VERSION 5.5 ;
NAMESCASESENSITIVE ON ;
BUSBITCHARS "[]" ;
DIVIDERCHAR "/" ;

PROPERTYDEFINITIONS
  LAYER routingPitch REAL ;
END PROPERTYDEFINITIONS

UNITS
  DATABASE MICRONS 1000 ;
END UNITS
MANUFACTURINGGRID 0.01 ;
LAYER POLY1
  TYPE MASTERSLICE ;
END POLY1

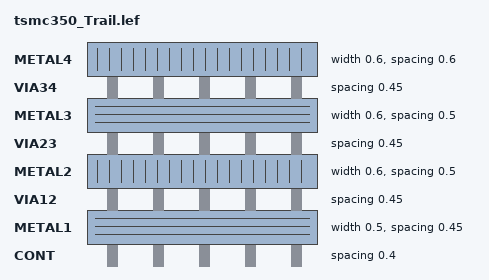
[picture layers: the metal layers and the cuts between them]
LAYER CONT
  TYPE CUT ;
  SPACING 0.4 ;
END CONT

LAYER METAL1
  TYPE ROUTING ;
  DIRECTION HORIZONTAL ;
  PITCH 0 ;
  WIDTH 0.5 ;
  SPACING 0.45 ;
  PROPERTY routingPitch 1.25 ;
END METAL1

LAYER VIA12
  TYPE CUT ;
  SPACING 0.45 ;
END VIA12

LAYER METAL2
  TYPE ROUTING ;
  DIRECTION VERTICAL ;
  PITCH 0 ;
  WIDTH 0.6 ;
  SPACING 0.5 ;
  PROPERTY routingPitch 1.4 ;
END METAL2

LAYER VIA23
  TYPE CUT ;
  SPACING 0.45 ;
END VIA23

LAYER METAL3
  TYPE ROUTING ;
  DIRECTION HORIZONTAL ;
  PITCH 0 ;
  WIDTH 0.6 ;
  SPACING 0.5 ;
  PROPERTY routingPitch 1.25 ;
END METAL3

LAYER VIA34
  TYPE CUT ;
  SPACING 0.45 ;
END VIA34

LAYER METAL4
  TYPE ROUTING ;
  DIRECTION VERTICAL ;
  PITCH 0 ;
  WIDTH 0.6 ;
  SPACING 0.6 ;
  PROPERTY routingPitch 1.4 ;
END METAL4

LAYER OVERLAP
  TYPE OVERLAP ;
END OVERLAP

VIARULE M4_M3 GENERATE
  LAYER METAL3 ;
    ENCLOSURE 0.2 0.2 ;
  LAYER METAL4 ;
    ENCLOSURE 0.15 0.15 ;
  LAYER VIA34 ;
    RECT -0.25 -0.25 0.25 0.25 ;
    SPACING 1 BY 1 ;
END M4_M3

VIARULE M3_M2 GENERATE
  LAYER METAL2 ;
    ENCLOSURE 0.2 0.2 ;
  LAYER METAL3 ;
    ENCLOSURE 0.15 0.15 ;
  LAYER VIA23 ;
    RECT -0.25 -0.25 0.25 0.25 ;
    SPACING 1 BY 1 ;
END M3_M2

VIARULE M2_M1 GENERATE
  LAYER METAL1 ;
    ENCLOSURE 0.2 0.2 ;
  LAYER METAL2 ;
    ENCLOSURE 0.15 0.15 ;
  LAYER VIA12 ;
    RECT -0.25 -0.25 0.25 0.25 ;
    SPACING 1 BY 1 ;
END M2_M1

VIARULE M1_POLY1 GENERATE
  LAYER POLY1 ;
    ENCLOSURE 0.2 0.2 ;
  LAYER METAL1 ;
    ENCLOSURE 0.15 0.15 ;
  LAYER CONT ;
    RECT -0.2 -0.2 0.2 0.2 ;
    SPACING 1 BY 1 ;
END M1_POLY1

VIA M1_POLY1
  LAYER CONT ;
    RECT -0.2 -0.2 0.2 0.2 ;
  LAYER POLY1 ;
    RECT -0.4 -0.4 0.4 0.4 ;
  LAYER METAL1 ;
    RECT -0.35 -0.35 0.35 0.35 ;
END M1_POLY1

VIA M2_M1
  LAYER VIA12 ;
    RECT -0.25 -0.25 0.25 0.25 ;
  LAYER METAL2 ;
    RECT -0.4 -0.4 0.4 0.4 ;
  LAYER METAL1 ;
    RECT -0.45 -0.45 0.45 0.45 ;
END M2_M1

VIA M3_M2
  LAYER VIA23 ;
    RECT -0.25 -0.25 0.25 0.25 ;
  LAYER METAL3 ;
    RECT -0.4 -0.4 0.4 0.4 ;
  LAYER METAL2 ;
    RECT -0.45 -0.45 0.45 0.45 ;
END M3_M2

VIA M4_M3
  LAYER VIA34 ;
    RECT -0.25 -0.25 0.25 0.25 ;
  LAYER METAL4 ;
    RECT -0.4 -0.4 0.4 0.4 ;
  LAYER METAL3 ;
    RECT -0.45 -0.45 0.45 0.45 ;
END M4_M3


MACRO TSMC350nm_TA2Cell_NoFG
  PIN VIN2_MINUS
    DIRECTION INOUT ;
    USE SIGNAL ;
    PORT
      LAYER METAL1 ;
        RECT 0.0 4.9 1.4 6.3 ;
    END
  END VIN2_MINUS
  PIN VD_P<0>
    DIRECTION INOUT ;
    USE SIGNAL ;
    PORT
      LAYER METAL1 ;
        RECT 0.0 16.1 1.4 17.5 ;
    END
  END VD_P<0>
  PIN OUTPUT<0>
    DIRECTION INOUT ;
    USE SIGNAL ;
    PORT
      LAYER METAL1 ;
        RECT 103.6 11.9 105.0 13.3 ;
    END
  END OUTPUT<0>
  PIN VD_P<1>
    DIRECTION INOUT ;
    USE SIGNAL ;
    PORT
      LAYER METAL1 ;
        RECT 0.0 0.7 1.395 2.1 ;
    END
  END VD_P<1>
  PIN VIN1_MINUS
    DIRECTION INOUT ;
    USE SIGNAL ;
    PORT
      LAYER METAL1 ;
        RECT 0.0 10.5 1.4 11.9 ;
    END
  END VIN1_MINUS
  PIN VIN1_PLUS
    DIRECTION INOUT ;
    USE SIGNAL ;
    PORT
      LAYER METAL1 ;
        RECT 0.0 13.3 1.4 14.7 ;
    END
  END VIN1_PLUS
  PIN VIN2_PLUS
    DIRECTION INOUT ;
    USE SIGNAL ;
    PORT
      LAYER METAL1 ;
        RECT 0.0 7.7 1.4 9.1 ;
    END
  END VIN2_PLUS
  PIN OUTPUT<1>
    DIRECTION INOUT ;
    USE SIGNAL ;
    PORT
      LAYER METAL1 ;
        RECT 103.6 7.7 105.0 9.1 ;
    END
  END OUTPUT<1>
  PIN VPWR_b
    DIRECTION INOUT ;
    USE SIGNAL ;
    PORT
      LAYER METAL2 ;
        RECT 93.1 0.0 94.5 1.4 ;
    END
  END VPWR_b
  PIN GND_b
    DIRECTION INOUT ;
    USE SIGNAL ;
    PORT
      LAYER METAL2 ;
        RECT 79.1 0.0 80.5 1.4 ;
    END
  END GND_b
  PIN VINJ_b
    DIRECTION INOUT ;
    USE SIGNAL ;
    PORT
      LAYER METAL2 ;
        RECT 44.1 0.0 45.5 1.4 ;
    END
  END VINJ_b
  PIN Vsel_b
    DIRECTION INOUT ;
    USE SIGNAL ;
    PORT
      LAYER METAL2 ;
        RECT 38.5 0.0 39.9 1.4 ;
    END
  END Vsel_b
  PIN Vsel
    DIRECTION INOUT ;
    USE SIGNAL ;
    PORT
      LAYER METAL2 ;
        RECT 38.5 20.6 39.9 22.0 ;
    END
  END Vsel
  PIN Vg_b
    DIRECTION INOUT ;
    USE SIGNAL ;
    PORT
      LAYER METAL2 ;
        RECT 10.5 0.0 11.9 1.4 ;
    END
  END Vg_b
  PIN VTUN
    DIRECTION INOUT ;
    USE SIGNAL ;
    PORT
      LAYER METAL2 ;
        RECT 2.1 20.605 3.5 22.0 ;
    END
  END VTUN
  PIN VINJ
    DIRECTION INOUT ;
    USE SIGNAL ;
    PORT
      LAYER METAL2 ;
        RECT 44.1 20.6 45.5 22.0 ;
    END
  END VINJ
  PIN VPWR
    DIRECTION INOUT ;
    USE SIGNAL ;
    PORT
      LAYER METAL2 ;
        RECT 93.1 20.6 94.5 22.0 ;
    END
  END VPWR
  PIN GND
    DIRECTION INOUT ;
    USE SIGNAL ;
    PORT
      LAYER METAL2 ;
        RECT 79.1 20.6 80.5 22.0 ;
    END
  END GND
  PIN VTUN_b
    DIRECTION INOUT ;
    USE SIGNAL ;
    PORT
      LAYER METAL2 ;
        RECT 2.1 0.0 3.5 1.395 ;
    END
  END VTUN_b
  PIN Vg
    DIRECTION INOUT ;
    USE SIGNAL ;
    PORT
      LAYER METAL2 ;
        RECT 10.5 20.6 11.9 22.0 ;
    END
  END Vg
END TSMC350nm_TA2Cell_NoFG

MACRO tile_analog_frame
  PIN n_Vg<0>
    DIRECTION INOUT ;
    USE SIGNAL ;
    PORT
      LAYER METAL3 ;
        RECT 3.64 225.2 5.04 228.0 ;
    END
  END n_Vg<0>
  PIN n_Vg<1>
    DIRECTION INOUT ;
    USE SIGNAL ;
    PORT
      LAYER METAL3 ;
        RECT 7.98 225.2 9.38 228.0 ;
    END
  END n_Vg<1>
  PIN n_Vg<2>
    DIRECTION INOUT ;
    USE SIGNAL ;
    PORT
      LAYER METAL3 ;
        RECT 12.32 225.2 13.72 228.0 ;
    END
  END n_Vg<2>
  PIN n_Vg<3>
    DIRECTION INOUT ;
    USE SIGNAL ;
    PORT
      LAYER METAL3 ;
        RECT 16.66 225.2 18.06 228.0 ;
    END
  END n_Vg<3>
  PIN n_Vg<4>
    DIRECTION INOUT ;
    USE SIGNAL ;
    PORT
      LAYER METAL3 ;
        RECT 21.0 225.2 22.4 228.0 ;
    END
  END n_Vg<4>
  PIN n_Vg<5>
    DIRECTION INOUT ;
    USE SIGNAL ;
    PORT
      LAYER METAL3 ;
        RECT 25.34 225.2 26.74 228.0 ;
    END
  END n_Vg<5>
  PIN n_Vg<6>
    DIRECTION INOUT ;
    USE SIGNAL ;
    PORT
      LAYER METAL3 ;
        RECT 29.68 225.2 31.08 228.0 ;
    END
  END n_Vg<6>
  PIN n_Vg<7>
    DIRECTION INOUT ;
    USE SIGNAL ;
    PORT
      LAYER METAL3 ;
        RECT 34.02 225.2 35.42 228.0 ;
    END
  END n_Vg<7>
  PIN n_Vg<8>
    DIRECTION INOUT ;
    USE SIGNAL ;
    PORT
      LAYER METAL3 ;
        RECT 38.36 225.2 39.76 228.0 ;
    END
  END n_Vg<8>
  PIN n_Vsel<0>
    DIRECTION INOUT ;
    USE SIGNAL ;
    PORT
      LAYER METAL3 ;
        RECT 42.7 225.2 44.1 228.0 ;
    END
  END n_Vsel<0>
  PIN n_Vsel<1>
    DIRECTION INOUT ;
    USE SIGNAL ;
    PORT
      LAYER METAL3 ;
        RECT 47.04 225.2 48.44 228.0 ;
    END
  END n_Vsel<1>
  PIN n_Vsel<2>
    DIRECTION INOUT ;
    USE SIGNAL ;
    PORT
      LAYER METAL3 ;
        RECT 51.38 225.2 52.78 228.0 ;
    END
  END n_Vsel<2>
  PIN n_Vsel<3>
    DIRECTION INOUT ;
    USE SIGNAL ;
    PORT
      LAYER METAL3 ;
        RECT 55.72 225.2 57.12 228.0 ;
    END
  END n_Vsel<3>
  PIN n_Vsel<4>
    DIRECTION INOUT ;
    USE SIGNAL ;
    PORT
      LAYER METAL3 ;
        RECT 60.06 225.2 61.46 228.0 ;
    END
  END n_Vsel<4>
  PIN n_Vsel<5>
    DIRECTION INOUT ;
    USE SIGNAL ;
    PORT
      LAYER METAL3 ;
        RECT 64.4 225.2 65.8 228.0 ;
    END
  END n_Vsel<5>
  PIN n_Vsel<6>
    DIRECTION INOUT ;
    USE SIGNAL ;
    PORT
      LAYER METAL3 ;
        RECT 68.74 225.2 70.14 228.0 ;
    END
  END n_Vsel<6>
  PIN n_Vsel<7>
    DIRECTION INOUT ;
    USE SIGNAL ;
    PORT
      LAYER METAL3 ;
        RECT 73.08 225.2 74.48 228.0 ;
    END
  END n_Vsel<7>
  PIN n_Vsel<8>
    DIRECTION INOUT ;
    USE SIGNAL ;
    PORT
      LAYER METAL3 ;
        RECT 77.42 225.2 78.82 228.0 ;
    END
  END n_Vsel<8>
  PIN e_Output<0>
    DIRECTION INOUT ;
    USE SIGNAL ;
    PORT
      LAYER METAL3 ;
        RECT 402.2 222.26 405.0 223.66 ;
    END
  END e_Output<0>
  PIN e_Output<1>
    DIRECTION INOUT ;
    USE SIGNAL ;
    PORT
      LAYER METAL3 ;
        RECT 402.2 217.92 405.0 219.32 ;
    END
  END e_Output<1>
  PIN e_Output<2>
    DIRECTION INOUT ;
    USE SIGNAL ;
    PORT
      LAYER METAL3 ;
        RECT 402.2 213.58 405.0 214.98 ;
    END
  END e_Output<2>
  PIN e_Output<3>
    DIRECTION INOUT ;
    USE SIGNAL ;
    PORT
      LAYER METAL3 ;
        RECT 402.2 209.24 405.0 210.64 ;
    END
  END e_Output<3>
  PIN e_Output<4>
    DIRECTION INOUT ;
    USE SIGNAL ;
    PORT
      LAYER METAL3 ;
        RECT 402.2 204.9 405.0 206.3 ;
    END
  END e_Output<4>
  PIN e_Output<5>
    DIRECTION INOUT ;
    USE SIGNAL ;
    PORT
      LAYER METAL3 ;
        RECT 402.2 200.56 405.0 201.96 ;
    END
  END e_Output<5>
  PIN e_Output<6>
    DIRECTION INOUT ;
    USE SIGNAL ;
    PORT
      LAYER METAL3 ;
        RECT 402.2 196.22 405.0 197.62 ;
    END
  END e_Output<6>
  PIN e_Output<7>
    DIRECTION INOUT ;
    USE SIGNAL ;
    PORT
      LAYER METAL3 ;
        RECT 402.2 191.88 405.0 193.28 ;
    END
  END e_Output<7>
  PIN w_Vd_P<0>
    DIRECTION INOUT ;
    USE SIGNAL ;
    PORT
      LAYER METAL3 ;
        RECT 0.0 222.26 2.8 223.66 ;
    END
  END w_Vd_P<0>
  PIN w_Vd_P<1>
    DIRECTION INOUT ;
    USE SIGNAL ;
    PORT
      LAYER METAL3 ;
        RECT 0.0 217.92 2.8 219.32 ;
    END
  END w_Vd_P<1>
  PIN w_Vd_P<2>
    DIRECTION INOUT ;
    USE SIGNAL ;
    PORT
      LAYER METAL3 ;
        RECT 0.0 213.58 2.8 214.98 ;
    END
  END w_Vd_P<2>
  PIN w_Vd_P<3>
    DIRECTION INOUT ;
    USE SIGNAL ;
    PORT
      LAYER METAL3 ;
        RECT 0.0 209.24 2.8 210.64 ;
    END
  END w_Vd_P<3>
  PIN w_Vd_P<4>
    DIRECTION INOUT ;
    USE SIGNAL ;
    PORT
      LAYER METAL3 ;
        RECT 0.0 204.9 2.8 206.3 ;
    END
  END w_Vd_P<4>
  PIN w_Vd_P<5>
    DIRECTION INOUT ;
    USE SIGNAL ;
    PORT
      LAYER METAL3 ;
        RECT 0.0 200.56 2.8 201.96 ;
    END
  END w_Vd_P<5>
  PIN w_Vd_P<6>
    DIRECTION INOUT ;
    USE SIGNAL ;
    PORT
      LAYER METAL3 ;
        RECT 0.0 196.22 2.8 197.62 ;
    END
  END w_Vd_P<6>
  PIN w_Vd_P<7>
    DIRECTION INOUT ;
    USE SIGNAL ;
    PORT
      LAYER METAL3 ;
        RECT 0.0 191.88 2.8 193.28 ;
    END
  END w_Vd_P<7>
  PIN w_Vd_P<8>
    DIRECTION INOUT ;
    USE SIGNAL ;
    PORT
      LAYER METAL3 ;
        RECT 0.0 187.54 2.8 188.94 ;
    END
  END w_Vd_P<8>
  PIN w_Vd_P<9>
    DIRECTION INOUT ;
    USE SIGNAL ;
    PORT
      LAYER METAL3 ;
        RECT 0.0 183.2 2.8 184.6 ;
    END
  END w_Vd_P<9>
  PIN w_Vd_P<10>
    DIRECTION INOUT ;
    USE SIGNAL ;
    PORT
      LAYER METAL3 ;
        RECT 0.0 178.86 2.8 180.26 ;
    END
  END w_Vd_P<10>
  PIN w_Vd_P<11>
    DIRECTION INOUT ;
    USE SIGNAL ;
    PORT
      LAYER METAL3 ;
        RECT 0.0 174.52 2.8 175.92 ;
    END
  END w_Vd_P<11>
  PIN w_Vd_P<12>
    DIRECTION INOUT ;
    USE SIGNAL ;
    PORT
      LAYER METAL3 ;
        RECT 0.0 170.18 2.8 171.58 ;
    END
  END w_Vd_P<12>
  PIN w_Vd_P<13>
    DIRECTION INOUT ;
    USE SIGNAL ;
    PORT
      LAYER METAL3 ;
        RECT 0.0 165.84 2.8 167.24 ;
    END
  END w_Vd_P<13>
  PIN w_Vd_P<14>
    DIRECTION INOUT ;
    USE SIGNAL ;
    PORT
      LAYER METAL3 ;
        RECT 0.0 161.5 2.8 162.9 ;
    END
  END w_Vd_P<14>
  PIN w_Vd_P<15>
    DIRECTION INOUT ;
    USE SIGNAL ;
    PORT
      LAYER METAL3 ;
        RECT 0.0 157.16 2.8 158.56 ;
    END
  END w_Vd_P<15>
END tile_analog_frame

MACRO TSMC350nm_4x2_Indirect
  PIN Vg<1>
    DIRECTION INOUT ;
    USE SIGNAL ;
    PORT
      LAYER METAL2 ;
        RECT 18.2 21.06 18.8 22.0 ;
    END
  END Vg<1>
  PIN Vsel<1>
    DIRECTION INOUT ;
    USE SIGNAL ;
    PORT
      LAYER METAL2 ;
        RECT 20.3 21.08 20.9 22.0 ;
    END
  END Vsel<1>
  PIN VINJ<1>
    DIRECTION INOUT ;
    USE SIGNAL ;
    PORT
      LAYER METAL2 ;
        RECT 22.4 21.05 23.0 22.0 ;
    END
  END VINJ<1>
  PIN Vsel<0>
    DIRECTION INOUT ;
    USE SIGNAL ;
    PORT
      LAYER METAL2 ;
        RECT 6.3 21.2 6.9 22.0 ;
    END
  END Vsel<0>
  PIN Vs<0>
    DIRECTION INOUT ;
    USE SIGNAL ;
    PORT
      LAYER METAL2 ;
        RECT 2.1 21.21 2.7 22.0 ;
    END
  END Vs<0>
  PIN Vs<1>
    DIRECTION INOUT ;
    USE SIGNAL ;
    PORT
      LAYER METAL2 ;
        RECT 24.5 21.06 25.1 22.0 ;
    END
  END Vs<1>
  PIN VTUN
    DIRECTION INOUT ;
    USE SIGNAL ;
    PORT
      LAYER METAL2 ;
        RECT 13.3 21.09 13.9 22.0 ;
    END
  END VTUN
  PIN VINJ<0>
    DIRECTION INOUT ;
    USE SIGNAL ;
    PORT
      LAYER METAL2 ;
        RECT 4.2 21.18 4.8 22.0 ;
    END
  END VINJ<0>
  PIN GND<0>
    DIRECTION INOUT ;
    USE SIGNAL ;
    PORT
      LAYER METAL2 ;
        RECT 11.2 21.07 11.8 22.0 ;
    END
  END GND<0>
  PIN Vg<0>
    DIRECTION INOUT ;
    USE SIGNAL ;
    PORT
      LAYER METAL2 ;
        RECT 8.4 21.03 9.0 22.0 ;
    END
  END Vg<0>
  PIN GND<1>
    DIRECTION INOUT ;
    USE SIGNAL ;
    PORT
      LAYER METAL2 ;
        RECT 15.41 21.06 16.01 22.0 ;
    END
  END GND<1>
  PIN Vs_b<0>
    DIRECTION INOUT ;
    USE SIGNAL ;
    PORT
      LAYER METAL2 ;
        RECT 1.42 0.0 2.7 0.6 ;
    END
  END Vs_b<0>
  PIN VINJ_b<0>
    DIRECTION INOUT ;
    USE SIGNAL ;
    PORT
      LAYER METAL2 ;
        RECT 4.2 0.0 4.8 0.76 ;
    END
  END VINJ_b<0>
  PIN Vsel_b<0>
    DIRECTION INOUT ;
    USE SIGNAL ;
    PORT
      LAYER METAL2 ;
        RECT 6.3 0.0 6.9 0.78 ;
    END
  END Vsel_b<0>
  PIN Vg_b<0>
    DIRECTION INOUT ;
    USE SIGNAL ;
    PORT
      LAYER METAL2 ;
        RECT 8.4 0.0 9.0 0.77 ;
    END
  END Vg_b<0>
  PIN GND_b<0>
    DIRECTION INOUT ;
    USE SIGNAL ;
    PORT
      LAYER METAL2 ;
        RECT 11.2 0.0 11.8 0.76 ;
    END
  END GND_b<0>
  PIN VTUN_b
    DIRECTION INOUT ;
    USE SIGNAL ;
    PORT
      LAYER METAL2 ;
        RECT 13.3 0.0 13.9 0.76 ;
    END
  END VTUN_b
  PIN GND_b<1>
    DIRECTION INOUT ;
    USE SIGNAL ;
    PORT
      LAYER METAL2 ;
        RECT 15.41 0.0 16.01 0.83 ;
    END
  END GND_b<1>
  PIN Vg_b<1>
    DIRECTION INOUT ;
    USE SIGNAL ;
    PORT
      LAYER METAL2 ;
        RECT 18.2 0.0 18.8 0.76 ;
    END
  END Vg_b<1>
  PIN Vsel_b<1>
    DIRECTION INOUT ;
    USE SIGNAL ;
    PORT
      LAYER METAL2 ;
        RECT 20.3 0.0 20.9 0.75 ;
    END
  END Vsel_b<1>
  PIN VINJ_b<1>
    DIRECTION INOUT ;
    USE SIGNAL ;
    PORT
      LAYER METAL2 ;
        RECT 22.4 0.0 23.0 0.77 ;
    END
  END VINJ_b<1>
  PIN Vs_b<1>
    DIRECTION INOUT ;
    USE SIGNAL ;
    PORT
      LAYER METAL2 ;
        RECT 24.5 0.0 25.75 0.61 ;
    END
  END Vs_b<1>
  PIN Vd_Pl<3>
    DIRECTION INOUT ;
    USE SIGNAL ;
    PORT
      LAYER METAL1 ;
        RECT 0.0 0.7 1.47 1.2 ;
    END
  END Vd_Pl<3>
  PIN Vd_Rl<3>
    DIRECTION INOUT ;
    USE SIGNAL ;
    PORT
      LAYER METAL1 ;
        RECT 0.0 3.5 1.45 4.0 ;
    END
  END Vd_Rl<3>
  PIN Vd_Rl<2>
    DIRECTION INOUT ;
    USE SIGNAL ;
    PORT
      LAYER METAL1 ;
        RECT 0.0 7.0 1.4 7.5 ;
    END
  END Vd_Rl<2>
  PIN Vd_Pl<2>
    DIRECTION INOUT ;
    USE SIGNAL ;
    PORT
      LAYER METAL1 ;
        RECT 0.0 9.8 1.41 10.3 ;
    END
  END Vd_Pl<2>
  PIN Vd_Pl<1>
    DIRECTION INOUT ;
    USE SIGNAL ;
    PORT
      LAYER METAL1 ;
        RECT 0.0 11.89 1.43 12.4 ;
    END
  END Vd_Pl<1>
  PIN Vd_Rl<1>
    DIRECTION INOUT ;
    USE SIGNAL ;
    PORT
      LAYER METAL1 ;
        RECT 0.0 14.7 1.46 15.2 ;
    END
  END Vd_Rl<1>
  PIN Vd_Rl<0>
    DIRECTION INOUT ;
    USE SIGNAL ;
    PORT
      LAYER METAL1 ;
        RECT 0.0 17.5 1.43 18.0 ;
    END
  END Vd_Rl<0>
  PIN Vd_Pl<0>
    DIRECTION INOUT ;
    USE SIGNAL ;
    PORT
      LAYER METAL1 ;
        RECT 0.0 20.3 1.4 20.9 ;
    END
  END Vd_Pl<0>
  PIN Vd_P<0>
    DIRECTION INOUT ;
    USE SIGNAL ;
    PORT
      LAYER METAL1 ;
        RECT 26.63 20.3 27.46 20.8 ;
    END
  END Vd_P<0>
  PIN Vd_R<1>
    DIRECTION INOUT ;
    USE SIGNAL ;
    PORT
      LAYER METAL1 ;
        RECT 26.56 14.7 27.44 15.2 ;
    END
  END Vd_R<1>
  PIN Vd_R<3>
    DIRECTION INOUT ;
    USE SIGNAL ;
    PORT
      LAYER METAL1 ;
        RECT 26.5 3.5 27.46 4.0 ;
    END
  END Vd_R<3>
  PIN Vd_P<3>
    DIRECTION INOUT ;
    USE SIGNAL ;
    PORT
      LAYER METAL1 ;
        RECT 26.55 0.7 27.46 1.2 ;
    END
  END Vd_P<3>
  PIN Vd_P<1>
    DIRECTION INOUT ;
    USE SIGNAL ;
    PORT
      LAYER METAL1 ;
        RECT 26.38 11.9 27.46 12.4 ;
    END
  END Vd_P<1>
  PIN Vd_P<2>
    DIRECTION INOUT ;
    USE SIGNAL ;
    PORT
      LAYER METAL1 ;
        RECT 26.51 9.8 27.46 10.3 ;
    END
  END Vd_P<2>
  PIN Vd_R<0>
    DIRECTION INOUT ;
    USE SIGNAL ;
    PORT
      LAYER METAL1 ;
        RECT 26.66 17.5 27.46 18.0 ;
    END
  END Vd_R<0>
  PIN Vd_R<2>
    DIRECTION INOUT ;
    USE SIGNAL ;
    PORT
      LAYER METAL1 ;
        RECT 26.53 7.0 27.46 7.5 ;
    END
  END Vd_R<2>
END TSMC350nm_4x2_Indirect

END LIBRARY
